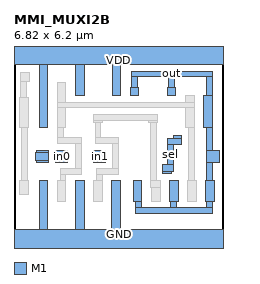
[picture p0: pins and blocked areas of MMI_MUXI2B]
MACRO MMI_MUXI2B
	CLASS CORE ;
	FOREIGN MMI_MUXI2B 0 0 ;
	SIZE 6.82 BY 6.2 ;
	SYMMETRY X Y ;
	SITE CORE1 ;
	PIN out
		DIRECTION output ;
		USE SIGNAL ;
		PORT
			LAYER M1 ;
			RECT 3.83 5.39 6.48 5.58 ;
			LAYER M1 ;
			RECT 3.83 5.045 4.02 5.39 ;
			LAYER M1 ;
			RECT 5.035 5.045 5.23 5.39 ;
			LAYER M1 ;
			RECT 3.795 4.765 4.075 5.045 ;
			LAYER M1 ;
			RECT 4.995 4.765 5.275 5.045 ;
			LAYER M1 ;
			RECT 6.285 4.79 6.48 5.39 ;
			LAYER M1 ;
			RECT 6.185 3.73 6.48 4.79 ;
			LAYER M1 ;
			RECT 6.285 2.98 6.48 3.73 ;
			LAYER M1 ;
			RECT 6.285 2.6 6.7 2.98 ;
			LAYER M1 ;
			RECT 6.285 2.02 6.48 2.6 ;
			LAYER M1 ;
			RECT 3.895 1.32 4.175 2.02 ;
			LAYER M1 ;
			RECT 5.075 1.32 5.355 2.02 ;
			LAYER M1 ;
			RECT 6.255 1.32 6.535 2.02 ;
			LAYER M1 ;
			RECT 3.98 1.11 4.17 1.32 ;
			LAYER M1 ;
			RECT 5.12 1.11 5.31 1.32 ;
			LAYER M1 ;
			RECT 6.285 1.11 6.48 1.32 ;
			LAYER M1 ;
			RECT 3.98 0.92 6.48 1.11 ;
		END
		AntennaDiffArea 2.8644 ;
	END out
	PIN in1
		DIRECTION input ;
		USE SIGNAL ;
		PORT
			LAYER M1 ;
			RECT 2.6 2.6 2.98 2.98 ;
		END
		AntennaGateArea 0.693 ;
	END in1
	PIN sel
		DIRECTION input ;
		USE SIGNAL ;
		PORT
			LAYER M1 ;
			RECT 5.2 3.37 5.48 3.46 ;
			LAYER M1 ;
			RECT 5.015 3.18 5.48 3.37 ;
			LAYER M1 ;
			RECT 0.74 2.935 1.12 2.98 ;
			LAYER M1 ;
			RECT 0.69 2.655 1.12 2.935 ;
			LAYER M1 ;
			RECT 0.74 2.6 1.12 2.655 ;
			LAYER M1 ;
			RECT 5.015 2.515 5.21 3.18 ;
			LAYER M1 ;
			RECT 4.845 2.29 5.21 2.515 ;
			LAYER M1 ;
			RECT 4.845 2.235 5.125 2.29 ;
		END
		AntennaGateArea 0.927 ;
	END sel
	PIN GND
		DIRECTION inout ;
		USE GROUND ;
		PORT
			LAYER M1 ;
			RECT 0.825 0.42 1.105 2.01 ;
			LAYER M1 ;
			RECT 2.005 0.42 2.285 2.01 ;
			LAYER M1 ;
			RECT 3.185 0.42 3.465 2.01 ;
			LAYER M1 ;
			RECT 0 -0.42 6.82 0.42 ;
		END
	END GND
	PIN VDD
		DIRECTION inout ;
		USE POWER ;
		PORT
			LAYER M1 ;
			RECT 0 5.78 6.82 6.62 ;
			LAYER M1 ;
			RECT 0.825 3.73 1.105 5.78 ;
			LAYER M1 ;
			RECT 2.005 4.765 2.285 5.78 ;
			LAYER M1 ;
			RECT 3.205 4.765 3.485 5.78 ;
		END
	END VDD
	PIN in0
		DIRECTION input ;
		USE SIGNAL ;
		PORT
			LAYER M1 ;
			RECT 1.36 2.6 1.74 2.98 ;
		END
		AntennaGateArea 0.693 ;
	END in0
	OBS
		LAYER M1 ;
		RECT 0.22 5.24 0.5 5.52 ;
		LAYER M1 ;
		RECT 0.22 4.7 0.41 5.24 ;
		LAYER M1 ;
		RECT 0.19 3.73 0.47 4.7 ;
		LAYER M1 ;
		RECT 1.415 4.565 1.695 5.2 ;
		LAYER M1 ;
		RECT 5.595 4.565 5.875 4.79 ;
		LAYER M1 ;
		RECT 1.415 4.375 5.875 4.565 ;
		LAYER M1 ;
		RECT 1.415 3.73 1.695 4.375 ;
		LAYER M1 ;
		RECT 2.6 4.15 2.88 4.175 ;
		LAYER M1 ;
		RECT 4.395 4.15 4.675 4.175 ;
		LAYER M1 ;
		RECT 2.6 3.96 4.675 4.15 ;
		LAYER M1 ;
		RECT 2.6 3.895 2.88 3.96 ;
		LAYER M1 ;
		RECT 4.395 3.895 4.675 3.96 ;
		LAYER M1 ;
		RECT 0.245 2.01 0.435 3.73 ;
		LAYER M1 ;
		RECT 1.435 3.405 1.625 3.73 ;
		LAYER M1 ;
		RECT 2.645 3.405 2.835 3.895 ;
		LAYER M1 ;
		RECT 1.435 3.215 2.205 3.405 ;
		LAYER M1 ;
		RECT 2.645 3.215 3.4 3.405 ;
		LAYER M1 ;
		RECT 2.01 2.4 2.205 3.215 ;
		LAYER M1 ;
		RECT 3.21 2.4 3.4 3.215 ;
		LAYER M1 ;
		RECT 1.505 2.21 2.205 2.4 ;
		LAYER M1 ;
		RECT 2.68 2.21 3.4 2.4 ;
		LAYER M1 ;
		RECT 1.505 2.01 1.695 2.21 ;
		LAYER M1 ;
		RECT 2.68 2.01 2.875 2.21 ;
		LAYER M1 ;
		RECT 4.455 2.02 4.645 3.895 ;
		LAYER M1 ;
		RECT 5.595 3.73 5.875 4.375 ;
		LAYER M1 ;
		RECT 5.68 2.02 5.875 3.73 ;
		LAYER M1 ;
		RECT 0.19 1.56 0.47 2.01 ;
		LAYER M1 ;
		RECT 1.415 1.31 1.695 2.01 ;
		LAYER M1 ;
		RECT 2.595 1.31 2.875 2.01 ;
		LAYER M1 ;
		RECT 4.455 1.785 4.765 2.02 ;
		LAYER M1 ;
		RECT 4.485 1.32 4.765 1.785 ;
		LAYER M1 ;
		RECT 5.665 1.32 5.945 2.02 ;
	END
END MMI_MUXI2B
